VERSION 5.7 ;
BUSBITCHARS "[]" ;
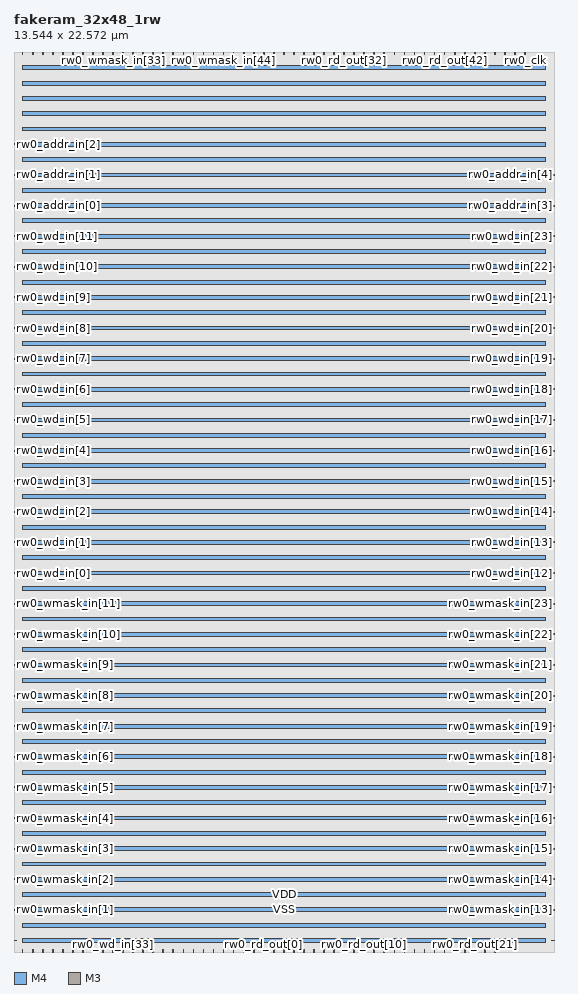
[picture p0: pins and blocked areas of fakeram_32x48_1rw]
MACRO fakeram_32x48_1rw
  FOREIGN fakeram_32x48_1rw 0 0 ;
  SYMMETRY X Y R90 ;
  SIZE 13.544 BY 22.572 ;
  CLASS BLOCK ;
  PIN rw0_wmask_in[0]
    DIRECTION INPUT ;
    USE SIGNAL ;
    SHAPE ABUTMENT ;
    PORT
      LAYER M4 ;
      RECT 0.000 0.276 0.072 0.300 ;
    END
  END rw0_wmask_in[0]
  PIN rw0_wmask_in[1]
    DIRECTION INPUT ;
    USE SIGNAL ;
    SHAPE ABUTMENT ;
    PORT
      LAYER M4 ;
      RECT 0.000 1.044 0.072 1.068 ;
    END
  END rw0_wmask_in[1]
  PIN rw0_wmask_in[2]
    DIRECTION INPUT ;
    USE SIGNAL ;
    SHAPE ABUTMENT ;
    PORT
      LAYER M4 ;
      RECT 0.000 1.812 0.072 1.836 ;
    END
  END rw0_wmask_in[2]
  PIN rw0_wmask_in[3]
    DIRECTION INPUT ;
    USE SIGNAL ;
    SHAPE ABUTMENT ;
    PORT
      LAYER M4 ;
      RECT 0.000 2.580 0.072 2.604 ;
    END
  END rw0_wmask_in[3]
  PIN rw0_wmask_in[4]
    DIRECTION INPUT ;
    USE SIGNAL ;
    SHAPE ABUTMENT ;
    PORT
      LAYER M4 ;
      RECT 0.000 3.348 0.072 3.372 ;
    END
  END rw0_wmask_in[4]
  PIN rw0_wmask_in[5]
    DIRECTION INPUT ;
    USE SIGNAL ;
    SHAPE ABUTMENT ;
    PORT
      LAYER M4 ;
      RECT 0.000 4.116 0.072 4.140 ;
    END
  END rw0_wmask_in[5]
  PIN rw0_wmask_in[6]
    DIRECTION INPUT ;
    USE SIGNAL ;
    SHAPE ABUTMENT ;
    PORT
      LAYER M4 ;
      RECT 0.000 4.884 0.072 4.908 ;
    END
  END rw0_wmask_in[6]
  PIN rw0_wmask_in[7]
    DIRECTION INPUT ;
    USE SIGNAL ;
    SHAPE ABUTMENT ;
    PORT
      LAYER M4 ;
      RECT 0.000 5.652 0.072 5.676 ;
    END
  END rw0_wmask_in[7]
  PIN rw0_wmask_in[8]
    DIRECTION INPUT ;
    USE SIGNAL ;
    SHAPE ABUTMENT ;
    PORT
      LAYER M4 ;
      RECT 0.000 6.420 0.072 6.444 ;
    END
  END rw0_wmask_in[8]
  PIN rw0_wmask_in[9]
    DIRECTION INPUT ;
    USE SIGNAL ;
    SHAPE ABUTMENT ;
    PORT
      LAYER M4 ;
      RECT 0.000 7.188 0.072 7.212 ;
    END
  END rw0_wmask_in[9]
  PIN rw0_wmask_in[10]
    DIRECTION INPUT ;
    USE SIGNAL ;
    SHAPE ABUTMENT ;
    PORT
      LAYER M4 ;
      RECT 0.000 7.956 0.072 7.980 ;
    END
  END rw0_wmask_in[10]
  PIN rw0_wmask_in[11]
    DIRECTION INPUT ;
    USE SIGNAL ;
    SHAPE ABUTMENT ;
    PORT
      LAYER M4 ;
      RECT 0.000 8.724 0.072 8.748 ;
    END
  END rw0_wmask_in[11]
  PIN rw0_wmask_in[12]
    DIRECTION INPUT ;
    USE SIGNAL ;
    SHAPE ABUTMENT ;
    PORT
      LAYER M4 ;
      RECT 13.472 0.276 13.544 0.300 ;
    END
  END rw0_wmask_in[12]
  PIN rw0_wmask_in[13]
    DIRECTION INPUT ;
    USE SIGNAL ;
    SHAPE ABUTMENT ;
    PORT
      LAYER M4 ;
      RECT 13.472 1.044 13.544 1.068 ;
    END
  END rw0_wmask_in[13]
  PIN rw0_wmask_in[14]
    DIRECTION INPUT ;
    USE SIGNAL ;
    SHAPE ABUTMENT ;
    PORT
      LAYER M4 ;
      RECT 13.472 1.812 13.544 1.836 ;
    END
  END rw0_wmask_in[14]
  PIN rw0_wmask_in[15]
    DIRECTION INPUT ;
    USE SIGNAL ;
    SHAPE ABUTMENT ;
    PORT
      LAYER M4 ;
      RECT 13.472 2.580 13.544 2.604 ;
    END
  END rw0_wmask_in[15]
  PIN rw0_wmask_in[16]
    DIRECTION INPUT ;
    USE SIGNAL ;
    SHAPE ABUTMENT ;
    PORT
      LAYER M4 ;
      RECT 13.472 3.348 13.544 3.372 ;
    END
  END rw0_wmask_in[16]
  PIN rw0_wmask_in[17]
    DIRECTION INPUT ;
    USE SIGNAL ;
    SHAPE ABUTMENT ;
    PORT
      LAYER M4 ;
      RECT 13.472 4.116 13.544 4.140 ;
    END
  END rw0_wmask_in[17]
  PIN rw0_wmask_in[18]
    DIRECTION INPUT ;
    USE SIGNAL ;
    SHAPE ABUTMENT ;
    PORT
      LAYER M4 ;
      RECT 13.472 4.884 13.544 4.908 ;
    END
  END rw0_wmask_in[18]
  PIN rw0_wmask_in[19]
    DIRECTION INPUT ;
    USE SIGNAL ;
    SHAPE ABUTMENT ;
    PORT
      LAYER M4 ;
      RECT 13.472 5.652 13.544 5.676 ;
    END
  END rw0_wmask_in[19]
  PIN rw0_wmask_in[20]
    DIRECTION INPUT ;
    USE SIGNAL ;
    SHAPE ABUTMENT ;
    PORT
      LAYER M4 ;
      RECT 13.472 6.420 13.544 6.444 ;
    END
  END rw0_wmask_in[20]
  PIN rw0_wmask_in[21]
    DIRECTION INPUT ;
    USE SIGNAL ;
    SHAPE ABUTMENT ;
    PORT
      LAYER M4 ;
      RECT 13.472 7.188 13.544 7.212 ;
    END
  END rw0_wmask_in[21]
  PIN rw0_wmask_in[22]
    DIRECTION INPUT ;
    USE SIGNAL ;
    SHAPE ABUTMENT ;
    PORT
      LAYER M4 ;
      RECT 13.472 7.956 13.544 7.980 ;
    END
  END rw0_wmask_in[22]
  PIN rw0_wmask_in[23]
    DIRECTION INPUT ;
    USE SIGNAL ;
    SHAPE ABUTMENT ;
    PORT
      LAYER M4 ;
      RECT 13.472 8.724 13.544 8.748 ;
    END
  END rw0_wmask_in[23]
  PIN rw0_wmask_in[24]
    DIRECTION INPUT ;
    USE SIGNAL ;
    SHAPE ABUTMENT ;
    PORT
      LAYER M3 ;
      RECT 0.207 22.518 0.225 22.572 ;
    END
  END rw0_wmask_in[24]
  PIN rw0_wmask_in[25]
    DIRECTION INPUT ;
    USE SIGNAL ;
    SHAPE ABUTMENT ;
    PORT
      LAYER M3 ;
      RECT 0.459 22.518 0.477 22.572 ;
    END
  END rw0_wmask_in[25]
  PIN rw0_wmask_in[26]
    DIRECTION INPUT ;
    USE SIGNAL ;
    SHAPE ABUTMENT ;
    PORT
      LAYER M3 ;
      RECT 0.711 22.518 0.729 22.572 ;
    END
  END rw0_wmask_in[26]
  PIN rw0_wmask_in[27]
    DIRECTION INPUT ;
    USE SIGNAL ;
    SHAPE ABUTMENT ;
    PORT
      LAYER M3 ;
      RECT 0.963 22.518 0.981 22.572 ;
    END
  END rw0_wmask_in[27]
  PIN rw0_wmask_in[28]
    DIRECTION INPUT ;
    USE SIGNAL ;
    SHAPE ABUTMENT ;
    PORT
      LAYER M3 ;
      RECT 1.215 22.518 1.233 22.572 ;
    END
  END rw0_wmask_in[28]
  PIN rw0_wmask_in[29]
    DIRECTION INPUT ;
    USE SIGNAL ;
    SHAPE ABUTMENT ;
    PORT
      LAYER M3 ;
      RECT 1.467 22.518 1.485 22.572 ;
    END
  END rw0_wmask_in[29]
  PIN rw0_wmask_in[30]
    DIRECTION INPUT ;
    USE SIGNAL ;
    SHAPE ABUTMENT ;
    PORT
      LAYER M3 ;
      RECT 1.719 22.518 1.737 22.572 ;
    END
  END rw0_wmask_in[30]
  PIN rw0_wmask_in[31]
    DIRECTION INPUT ;
    USE SIGNAL ;
    SHAPE ABUTMENT ;
    PORT
      LAYER M3 ;
      RECT 1.971 22.518 1.989 22.572 ;
    END
  END rw0_wmask_in[31]
  PIN rw0_wmask_in[32]
    DIRECTION INPUT ;
    USE SIGNAL ;
    SHAPE ABUTMENT ;
    PORT
      LAYER M3 ;
      RECT 2.223 22.518 2.241 22.572 ;
    END
  END rw0_wmask_in[32]
  PIN rw0_wmask_in[33]
    DIRECTION INPUT ;
    USE SIGNAL ;
    SHAPE ABUTMENT ;
    PORT
      LAYER M3 ;
      RECT 2.475 22.518 2.493 22.572 ;
    END
  END rw0_wmask_in[33]
  PIN rw0_wmask_in[34]
    DIRECTION INPUT ;
    USE SIGNAL ;
    SHAPE ABUTMENT ;
    PORT
      LAYER M3 ;
      RECT 2.727 22.518 2.745 22.572 ;
    END
  END rw0_wmask_in[34]
  PIN rw0_wmask_in[35]
    DIRECTION INPUT ;
    USE SIGNAL ;
    SHAPE ABUTMENT ;
    PORT
      LAYER M3 ;
      RECT 2.979 22.518 2.997 22.572 ;
    END
  END rw0_wmask_in[35]
  PIN rw0_wmask_in[36]
    DIRECTION INPUT ;
    USE SIGNAL ;
    SHAPE ABUTMENT ;
    PORT
      LAYER M3 ;
      RECT 3.231 22.518 3.249 22.572 ;
    END
  END rw0_wmask_in[36]
  PIN rw0_wmask_in[37]
    DIRECTION INPUT ;
    USE SIGNAL ;
    SHAPE ABUTMENT ;
    PORT
      LAYER M3 ;
      RECT 3.483 22.518 3.501 22.572 ;
    END
  END rw0_wmask_in[37]
  PIN rw0_wmask_in[38]
    DIRECTION INPUT ;
    USE SIGNAL ;
    SHAPE ABUTMENT ;
    PORT
      LAYER M3 ;
      RECT 3.735 22.518 3.753 22.572 ;
    END
  END rw0_wmask_in[38]
  PIN rw0_wmask_in[39]
    DIRECTION INPUT ;
    USE SIGNAL ;
    SHAPE ABUTMENT ;
    PORT
      LAYER M3 ;
      RECT 3.987 22.518 4.005 22.572 ;
    END
  END rw0_wmask_in[39]
  PIN rw0_wmask_in[40]
    DIRECTION INPUT ;
    USE SIGNAL ;
    SHAPE ABUTMENT ;
    PORT
      LAYER M3 ;
      RECT 4.239 22.518 4.257 22.572 ;
    END
  END rw0_wmask_in[40]
  PIN rw0_wmask_in[41]
    DIRECTION INPUT ;
    USE SIGNAL ;
    SHAPE ABUTMENT ;
    PORT
      LAYER M3 ;
      RECT 4.491 22.518 4.509 22.572 ;
    END
  END rw0_wmask_in[41]
  PIN rw0_wmask_in[42]
    DIRECTION INPUT ;
    USE SIGNAL ;
    SHAPE ABUTMENT ;
    PORT
      LAYER M3 ;
      RECT 4.743 22.518 4.761 22.572 ;
    END
  END rw0_wmask_in[42]
  PIN rw0_wmask_in[43]
    DIRECTION INPUT ;
    USE SIGNAL ;
    SHAPE ABUTMENT ;
    PORT
      LAYER M3 ;
      RECT 4.995 22.518 5.013 22.572 ;
    END
  END rw0_wmask_in[43]
  PIN rw0_wmask_in[44]
    DIRECTION INPUT ;
    USE SIGNAL ;
    SHAPE ABUTMENT ;
    PORT
      LAYER M3 ;
      RECT 5.247 22.518 5.265 22.572 ;
    END
  END rw0_wmask_in[44]
  PIN rw0_wmask_in[45]
    DIRECTION INPUT ;
    USE SIGNAL ;
    SHAPE ABUTMENT ;
    PORT
      LAYER M3 ;
      RECT 5.499 22.518 5.517 22.572 ;
    END
  END rw0_wmask_in[45]
  PIN rw0_wmask_in[46]
    DIRECTION INPUT ;
    USE SIGNAL ;
    SHAPE ABUTMENT ;
    PORT
      LAYER M3 ;
      RECT 5.751 22.518 5.769 22.572 ;
    END
  END rw0_wmask_in[46]
  PIN rw0_wmask_in[47]
    DIRECTION INPUT ;
    USE SIGNAL ;
    SHAPE ABUTMENT ;
    PORT
      LAYER M3 ;
      RECT 6.003 22.518 6.021 22.572 ;
    END
  END rw0_wmask_in[47]
  PIN rw0_wd_in[0]
    DIRECTION INPUT ;
    USE SIGNAL ;
    SHAPE ABUTMENT ;
    PORT
      LAYER M4 ;
      RECT 0.000 9.492 0.072 9.516 ;
    END
  END rw0_wd_in[0]
  PIN rw0_wd_in[1]
    DIRECTION INPUT ;
    USE SIGNAL ;
    SHAPE ABUTMENT ;
    PORT
      LAYER M4 ;
      RECT 0.000 10.260 0.072 10.284 ;
    END
  END rw0_wd_in[1]
  PIN rw0_wd_in[2]
    DIRECTION INPUT ;
    USE SIGNAL ;
    SHAPE ABUTMENT ;
    PORT
      LAYER M4 ;
      RECT 0.000 11.028 0.072 11.052 ;
    END
  END rw0_wd_in[2]
  PIN rw0_wd_in[3]
    DIRECTION INPUT ;
    USE SIGNAL ;
    SHAPE ABUTMENT ;
    PORT
      LAYER M4 ;
      RECT 0.000 11.796 0.072 11.820 ;
    END
  END rw0_wd_in[3]
  PIN rw0_wd_in[4]
    DIRECTION INPUT ;
    USE SIGNAL ;
    SHAPE ABUTMENT ;
    PORT
      LAYER M4 ;
      RECT 0.000 12.564 0.072 12.588 ;
    END
  END rw0_wd_in[4]
  PIN rw0_wd_in[5]
    DIRECTION INPUT ;
    USE SIGNAL ;
    SHAPE ABUTMENT ;
    PORT
      LAYER M4 ;
      RECT 0.000 13.332 0.072 13.356 ;
    END
  END rw0_wd_in[5]
  PIN rw0_wd_in[6]
    DIRECTION INPUT ;
    USE SIGNAL ;
    SHAPE ABUTMENT ;
    PORT
      LAYER M4 ;
      RECT 0.000 14.100 0.072 14.124 ;
    END
  END rw0_wd_in[6]
  PIN rw0_wd_in[7]
    DIRECTION INPUT ;
    USE SIGNAL ;
    SHAPE ABUTMENT ;
    PORT
      LAYER M4 ;
      RECT 0.000 14.868 0.072 14.892 ;
    END
  END rw0_wd_in[7]
  PIN rw0_wd_in[8]
    DIRECTION INPUT ;
    USE SIGNAL ;
    SHAPE ABUTMENT ;
    PORT
      LAYER M4 ;
      RECT 0.000 15.636 0.072 15.660 ;
    END
  END rw0_wd_in[8]
  PIN rw0_wd_in[9]
    DIRECTION INPUT ;
    USE SIGNAL ;
    SHAPE ABUTMENT ;
    PORT
      LAYER M4 ;
      RECT 0.000 16.404 0.072 16.428 ;
    END
  END rw0_wd_in[9]
  PIN rw0_wd_in[10]
    DIRECTION INPUT ;
    USE SIGNAL ;
    SHAPE ABUTMENT ;
    PORT
      LAYER M4 ;
      RECT 0.000 17.172 0.072 17.196 ;
    END
  END rw0_wd_in[10]
  PIN rw0_wd_in[11]
    DIRECTION INPUT ;
    USE SIGNAL ;
    SHAPE ABUTMENT ;
    PORT
      LAYER M4 ;
      RECT 0.000 17.940 0.072 17.964 ;
    END
  END rw0_wd_in[11]
  PIN rw0_wd_in[12]
    DIRECTION INPUT ;
    USE SIGNAL ;
    SHAPE ABUTMENT ;
    PORT
      LAYER M4 ;
      RECT 13.472 9.492 13.544 9.516 ;
    END
  END rw0_wd_in[12]
  PIN rw0_wd_in[13]
    DIRECTION INPUT ;
    USE SIGNAL ;
    SHAPE ABUTMENT ;
    PORT
      LAYER M4 ;
      RECT 13.472 10.260 13.544 10.284 ;
    END
  END rw0_wd_in[13]
  PIN rw0_wd_in[14]
    DIRECTION INPUT ;
    USE SIGNAL ;
    SHAPE ABUTMENT ;
    PORT
      LAYER M4 ;
      RECT 13.472 11.028 13.544 11.052 ;
    END
  END rw0_wd_in[14]
  PIN rw0_wd_in[15]
    DIRECTION INPUT ;
    USE SIGNAL ;
    SHAPE ABUTMENT ;
    PORT
      LAYER M4 ;
      RECT 13.472 11.796 13.544 11.820 ;
    END
  END rw0_wd_in[15]
  PIN rw0_wd_in[16]
    DIRECTION INPUT ;
    USE SIGNAL ;
    SHAPE ABUTMENT ;
    PORT
      LAYER M4 ;
      RECT 13.472 12.564 13.544 12.588 ;
    END
  END rw0_wd_in[16]
  PIN rw0_wd_in[17]
    DIRECTION INPUT ;
    USE SIGNAL ;
    SHAPE ABUTMENT ;
    PORT
      LAYER M4 ;
      RECT 13.472 13.332 13.544 13.356 ;
    END
  END rw0_wd_in[17]
  PIN rw0_wd_in[18]
    DIRECTION INPUT ;
    USE SIGNAL ;
    SHAPE ABUTMENT ;
    PORT
      LAYER M4 ;
      RECT 13.472 14.100 13.544 14.124 ;
    END
  END rw0_wd_in[18]
  PIN rw0_wd_in[19]
    DIRECTION INPUT ;
    USE SIGNAL ;
    SHAPE ABUTMENT ;
    PORT
      LAYER M4 ;
      RECT 13.472 14.868 13.544 14.892 ;
    END
  END rw0_wd_in[19]
  PIN rw0_wd_in[20]
    DIRECTION INPUT ;
    USE SIGNAL ;
    SHAPE ABUTMENT ;
    PORT
      LAYER M4 ;
      RECT 13.472 15.636 13.544 15.660 ;
    END
  END rw0_wd_in[20]
  PIN rw0_wd_in[21]
    DIRECTION INPUT ;
    USE SIGNAL ;
    SHAPE ABUTMENT ;
    PORT
      LAYER M4 ;
      RECT 13.472 16.404 13.544 16.428 ;
    END
  END rw0_wd_in[21]
  PIN rw0_wd_in[22]
    DIRECTION INPUT ;
    USE SIGNAL ;
    SHAPE ABUTMENT ;
    PORT
      LAYER M4 ;
      RECT 13.472 17.172 13.544 17.196 ;
    END
  END rw0_wd_in[22]
  PIN rw0_wd_in[23]
    DIRECTION INPUT ;
    USE SIGNAL ;
    SHAPE ABUTMENT ;
    PORT
      LAYER M4 ;
      RECT 13.472 17.940 13.544 17.964 ;
    END
  END rw0_wd_in[23]
  PIN rw0_wd_in[24]
    DIRECTION INPUT ;
    USE SIGNAL ;
    SHAPE ABUTMENT ;
    PORT
      LAYER M3 ;
      RECT 0.207 0.000 0.225 0.054 ;
    END
  END rw0_wd_in[24]
  PIN rw0_wd_in[25]
    DIRECTION INPUT ;
    USE SIGNAL ;
    SHAPE ABUTMENT ;
    PORT
      LAYER M3 ;
      RECT 0.459 0.000 0.477 0.054 ;
    END
  END rw0_wd_in[25]
  PIN rw0_wd_in[26]
    DIRECTION INPUT ;
    USE SIGNAL ;
    SHAPE ABUTMENT ;
    PORT
      LAYER M3 ;
      RECT 0.711 0.000 0.729 0.054 ;
    END
  END rw0_wd_in[26]
  PIN rw0_wd_in[27]
    DIRECTION INPUT ;
    USE SIGNAL ;
    SHAPE ABUTMENT ;
    PORT
      LAYER M3 ;
      RECT 0.963 0.000 0.981 0.054 ;
    END
  END rw0_wd_in[27]
  PIN rw0_wd_in[28]
    DIRECTION INPUT ;
    USE SIGNAL ;
    SHAPE ABUTMENT ;
    PORT
      LAYER M3 ;
      RECT 1.215 0.000 1.233 0.054 ;
    END
  END rw0_wd_in[28]
  PIN rw0_wd_in[29]
    DIRECTION INPUT ;
    USE SIGNAL ;
    SHAPE ABUTMENT ;
    PORT
      LAYER M3 ;
      RECT 1.467 0.000 1.485 0.054 ;
    END
  END rw0_wd_in[29]
  PIN rw0_wd_in[30]
    DIRECTION INPUT ;
    USE SIGNAL ;
    SHAPE ABUTMENT ;
    PORT
      LAYER M3 ;
      RECT 1.719 0.000 1.737 0.054 ;
    END
  END rw0_wd_in[30]
  PIN rw0_wd_in[31]
    DIRECTION INPUT ;
    USE SIGNAL ;
    SHAPE ABUTMENT ;
    PORT
      LAYER M3 ;
      RECT 1.971 0.000 1.989 0.054 ;
    END
  END rw0_wd_in[31]
  PIN rw0_wd_in[32]
    DIRECTION INPUT ;
    USE SIGNAL ;
    SHAPE ABUTMENT ;
    PORT
      LAYER M3 ;
      RECT 2.223 0.000 2.241 0.054 ;
    END
  END rw0_wd_in[32]
  PIN rw0_wd_in[33]
    DIRECTION INPUT ;
    USE SIGNAL ;
    SHAPE ABUTMENT ;
    PORT
      LAYER M3 ;
      RECT 2.475 0.000 2.493 0.054 ;
    END
  END rw0_wd_in[33]
  PIN rw0_wd_in[34]
    DIRECTION INPUT ;
    USE SIGNAL ;
    SHAPE ABUTMENT ;
    PORT
      LAYER M3 ;
      RECT 2.727 0.000 2.745 0.054 ;
    END
  END rw0_wd_in[34]
  PIN rw0_wd_in[35]
    DIRECTION INPUT ;
    USE SIGNAL ;
    SHAPE ABUTMENT ;
    PORT
      LAYER M3 ;
      RECT 2.979 0.000 2.997 0.054 ;
    END
  END rw0_wd_in[35]
  PIN rw0_wd_in[36]
    DIRECTION INPUT ;
    USE SIGNAL ;
    SHAPE ABUTMENT ;
    PORT
      LAYER M3 ;
      RECT 3.231 0.000 3.249 0.054 ;
    END
  END rw0_wd_in[36]
  PIN rw0_wd_in[37]
    DIRECTION INPUT ;
    USE SIGNAL ;
    SHAPE ABUTMENT ;
    PORT
      LAYER M3 ;
      RECT 3.483 0.000 3.501 0.054 ;
    END
  END rw0_wd_in[37]
  PIN rw0_wd_in[38]
    DIRECTION INPUT ;
    USE SIGNAL ;
    SHAPE ABUTMENT ;
    PORT
      LAYER M3 ;
      RECT 3.735 0.000 3.753 0.054 ;
    END
  END rw0_wd_in[38]
  PIN rw0_wd_in[39]
    DIRECTION INPUT ;
    USE SIGNAL ;
    SHAPE ABUTMENT ;
    PORT
      LAYER M3 ;
      RECT 3.987 0.000 4.005 0.054 ;
    END
  END rw0_wd_in[39]
  PIN rw0_wd_in[40]
    DIRECTION INPUT ;
    USE SIGNAL ;
    SHAPE ABUTMENT ;
    PORT
      LAYER M3 ;
      RECT 4.239 0.000 4.257 0.054 ;
    END
  END rw0_wd_in[40]
  PIN rw0_wd_in[41]
    DIRECTION INPUT ;
    USE SIGNAL ;
    SHAPE ABUTMENT ;
    PORT
      LAYER M3 ;
      RECT 4.491 0.000 4.509 0.054 ;
    END
  END rw0_wd_in[41]
  PIN rw0_wd_in[42]
    DIRECTION INPUT ;
    USE SIGNAL ;
    SHAPE ABUTMENT ;
    PORT
      LAYER M3 ;
      RECT 4.743 0.000 4.761 0.054 ;
    END
  END rw0_wd_in[42]
  PIN rw0_wd_in[43]
    DIRECTION INPUT ;
    USE SIGNAL ;
    SHAPE ABUTMENT ;
    PORT
      LAYER M3 ;
      RECT 4.995 0.000 5.013 0.054 ;
    END
  END rw0_wd_in[43]
  PIN rw0_wd_in[44]
    DIRECTION INPUT ;
    USE SIGNAL ;
    SHAPE ABUTMENT ;
    PORT
      LAYER M3 ;
      RECT 5.247 0.000 5.265 0.054 ;
    END
  END rw0_wd_in[44]
  PIN rw0_wd_in[45]
    DIRECTION INPUT ;
    USE SIGNAL ;
    SHAPE ABUTMENT ;
    PORT
      LAYER M3 ;
      RECT 5.499 0.000 5.517 0.054 ;
    END
  END rw0_wd_in[45]
  PIN rw0_wd_in[46]
    DIRECTION INPUT ;
    USE SIGNAL ;
    SHAPE ABUTMENT ;
    PORT
      LAYER M3 ;
      RECT 5.751 0.000 5.769 0.054 ;
    END
  END rw0_wd_in[46]
  PIN rw0_wd_in[47]
    DIRECTION INPUT ;
    USE SIGNAL ;
    SHAPE ABUTMENT ;
    PORT
      LAYER M3 ;
      RECT 6.003 0.000 6.021 0.054 ;
    END
  END rw0_wd_in[47]
  PIN rw0_rd_out[0]
    DIRECTION OUTPUT ;
    USE SIGNAL ;
    SHAPE ABUTMENT ;
    PORT
      LAYER M3 ;
      RECT 6.255 0.000 6.273 0.054 ;
    END
  END rw0_rd_out[0]
  PIN rw0_rd_out[1]
    DIRECTION OUTPUT ;
    USE SIGNAL ;
    SHAPE ABUTMENT ;
    PORT
      LAYER M3 ;
      RECT 6.507 0.000 6.525 0.054 ;
    END
  END rw0_rd_out[1]
  PIN rw0_rd_out[2]
    DIRECTION OUTPUT ;
    USE SIGNAL ;
    SHAPE ABUTMENT ;
    PORT
      LAYER M3 ;
      RECT 6.759 0.000 6.777 0.054 ;
    END
  END rw0_rd_out[2]
  PIN rw0_rd_out[3]
    DIRECTION OUTPUT ;
    USE SIGNAL ;
    SHAPE ABUTMENT ;
    PORT
      LAYER M3 ;
      RECT 7.011 0.000 7.029 0.054 ;
    END
  END rw0_rd_out[3]
  PIN rw0_rd_out[4]
    DIRECTION OUTPUT ;
    USE SIGNAL ;
    SHAPE ABUTMENT ;
    PORT
      LAYER M3 ;
      RECT 7.263 0.000 7.281 0.054 ;
    END
  END rw0_rd_out[4]
  PIN rw0_rd_out[5]
    DIRECTION OUTPUT ;
    USE SIGNAL ;
    SHAPE ABUTMENT ;
    PORT
      LAYER M3 ;
      RECT 7.515 0.000 7.533 0.054 ;
    END
  END rw0_rd_out[5]
  PIN rw0_rd_out[6]
    DIRECTION OUTPUT ;
    USE SIGNAL ;
    SHAPE ABUTMENT ;
    PORT
      LAYER M3 ;
      RECT 7.767 0.000 7.785 0.054 ;
    END
  END rw0_rd_out[6]
  PIN rw0_rd_out[7]
    DIRECTION OUTPUT ;
    USE SIGNAL ;
    SHAPE ABUTMENT ;
    PORT
      LAYER M3 ;
      RECT 8.019 0.000 8.037 0.054 ;
    END
  END rw0_rd_out[7]
  PIN rw0_rd_out[8]
    DIRECTION OUTPUT ;
    USE SIGNAL ;
    SHAPE ABUTMENT ;
    PORT
      LAYER M3 ;
      RECT 8.271 0.000 8.289 0.054 ;
    END
  END rw0_rd_out[8]
  PIN rw0_rd_out[9]
    DIRECTION OUTPUT ;
    USE SIGNAL ;
    SHAPE ABUTMENT ;
    PORT
      LAYER M3 ;
      RECT 8.523 0.000 8.541 0.054 ;
    END
  END rw0_rd_out[9]
  PIN rw0_rd_out[10]
    DIRECTION OUTPUT ;
    USE SIGNAL ;
    SHAPE ABUTMENT ;
    PORT
      LAYER M3 ;
      RECT 8.775 0.000 8.793 0.054 ;
    END
  END rw0_rd_out[10]
  PIN rw0_rd_out[11]
    DIRECTION OUTPUT ;
    USE SIGNAL ;
    SHAPE ABUTMENT ;
    PORT
      LAYER M3 ;
      RECT 9.027 0.000 9.045 0.054 ;
    END
  END rw0_rd_out[11]
  PIN rw0_rd_out[12]
    DIRECTION OUTPUT ;
    USE SIGNAL ;
    SHAPE ABUTMENT ;
    PORT
      LAYER M3 ;
      RECT 9.279 0.000 9.297 0.054 ;
    END
  END rw0_rd_out[12]
  PIN rw0_rd_out[13]
    DIRECTION OUTPUT ;
    USE SIGNAL ;
    SHAPE ABUTMENT ;
    PORT
      LAYER M3 ;
      RECT 9.531 0.000 9.549 0.054 ;
    END
  END rw0_rd_out[13]
  PIN rw0_rd_out[14]
    DIRECTION OUTPUT ;
    USE SIGNAL ;
    SHAPE ABUTMENT ;
    PORT
      LAYER M3 ;
      RECT 9.783 0.000 9.801 0.054 ;
    END
  END rw0_rd_out[14]
  PIN rw0_rd_out[15]
    DIRECTION OUTPUT ;
    USE SIGNAL ;
    SHAPE ABUTMENT ;
    PORT
      LAYER M3 ;
      RECT 10.035 0.000 10.053 0.054 ;
    END
  END rw0_rd_out[15]
  PIN rw0_rd_out[16]
    DIRECTION OUTPUT ;
    USE SIGNAL ;
    SHAPE ABUTMENT ;
    PORT
      LAYER M3 ;
      RECT 10.287 0.000 10.305 0.054 ;
    END
  END rw0_rd_out[16]
  PIN rw0_rd_out[17]
    DIRECTION OUTPUT ;
    USE SIGNAL ;
    SHAPE ABUTMENT ;
    PORT
      LAYER M3 ;
      RECT 10.539 0.000 10.557 0.054 ;
    END
  END rw0_rd_out[17]
  PIN rw0_rd_out[18]
    DIRECTION OUTPUT ;
    USE SIGNAL ;
    SHAPE ABUTMENT ;
    PORT
      LAYER M3 ;
      RECT 10.791 0.000 10.809 0.054 ;
    END
  END rw0_rd_out[18]
  PIN rw0_rd_out[19]
    DIRECTION OUTPUT ;
    USE SIGNAL ;
    SHAPE ABUTMENT ;
    PORT
      LAYER M3 ;
      RECT 11.043 0.000 11.061 0.054 ;
    END
  END rw0_rd_out[19]
  PIN rw0_rd_out[20]
    DIRECTION OUTPUT ;
    USE SIGNAL ;
    SHAPE ABUTMENT ;
    PORT
      LAYER M3 ;
      RECT 11.295 0.000 11.313 0.054 ;
    END
  END rw0_rd_out[20]
  PIN rw0_rd_out[21]
    DIRECTION OUTPUT ;
    USE SIGNAL ;
    SHAPE ABUTMENT ;
    PORT
      LAYER M3 ;
      RECT 11.547 0.000 11.565 0.054 ;
    END
  END rw0_rd_out[21]
  PIN rw0_rd_out[22]
    DIRECTION OUTPUT ;
    USE SIGNAL ;
    SHAPE ABUTMENT ;
    PORT
      LAYER M3 ;
      RECT 11.799 0.000 11.817 0.054 ;
    END
  END rw0_rd_out[22]
  PIN rw0_rd_out[23]
    DIRECTION OUTPUT ;
    USE SIGNAL ;
    SHAPE ABUTMENT ;
    PORT
      LAYER M3 ;
      RECT 12.051 0.000 12.069 0.054 ;
    END
  END rw0_rd_out[23]
  PIN rw0_rd_out[24]
    DIRECTION OUTPUT ;
    USE SIGNAL ;
    SHAPE ABUTMENT ;
    PORT
      LAYER M3 ;
      RECT 6.255 22.518 6.273 22.572 ;
    END
  END rw0_rd_out[24]
  PIN rw0_rd_out[25]
    DIRECTION OUTPUT ;
    USE SIGNAL ;
    SHAPE ABUTMENT ;
    PORT
      LAYER M3 ;
      RECT 6.507 22.518 6.525 22.572 ;
    END
  END rw0_rd_out[25]
  PIN rw0_rd_out[26]
    DIRECTION OUTPUT ;
    USE SIGNAL ;
    SHAPE ABUTMENT ;
    PORT
      LAYER M3 ;
      RECT 6.759 22.518 6.777 22.572 ;
    END
  END rw0_rd_out[26]
  PIN rw0_rd_out[27]
    DIRECTION OUTPUT ;
    USE SIGNAL ;
    SHAPE ABUTMENT ;
    PORT
      LAYER M3 ;
      RECT 7.011 22.518 7.029 22.572 ;
    END
  END rw0_rd_out[27]
  PIN rw0_rd_out[28]
    DIRECTION OUTPUT ;
    USE SIGNAL ;
    SHAPE ABUTMENT ;
    PORT
      LAYER M3 ;
      RECT 7.263 22.518 7.281 22.572 ;
    END
  END rw0_rd_out[28]
  PIN rw0_rd_out[29]
    DIRECTION OUTPUT ;
    USE SIGNAL ;
    SHAPE ABUTMENT ;
    PORT
      LAYER M3 ;
      RECT 7.515 22.518 7.533 22.572 ;
    END
  END rw0_rd_out[29]
  PIN rw0_rd_out[30]
    DIRECTION OUTPUT ;
    USE SIGNAL ;
    SHAPE ABUTMENT ;
    PORT
      LAYER M3 ;
      RECT 7.767 22.518 7.785 22.572 ;
    END
  END rw0_rd_out[30]
  PIN rw0_rd_out[31]
    DIRECTION OUTPUT ;
    USE SIGNAL ;
    SHAPE ABUTMENT ;
    PORT
      LAYER M3 ;
      RECT 8.019 22.518 8.037 22.572 ;
    END
  END rw0_rd_out[31]
  PIN rw0_rd_out[32]
    DIRECTION OUTPUT ;
    USE SIGNAL ;
    SHAPE ABUTMENT ;
    PORT
      LAYER M3 ;
      RECT 8.271 22.518 8.289 22.572 ;
    END
  END rw0_rd_out[32]
  PIN rw0_rd_out[33]
    DIRECTION OUTPUT ;
    USE SIGNAL ;
    SHAPE ABUTMENT ;
    PORT
      LAYER M3 ;
      RECT 8.523 22.518 8.541 22.572 ;
    END
  END rw0_rd_out[33]
  PIN rw0_rd_out[34]
    DIRECTION OUTPUT ;
    USE SIGNAL ;
    SHAPE ABUTMENT ;
    PORT
      LAYER M3 ;
      RECT 8.775 22.518 8.793 22.572 ;
    END
  END rw0_rd_out[34]
  PIN rw0_rd_out[35]
    DIRECTION OUTPUT ;
    USE SIGNAL ;
    SHAPE ABUTMENT ;
    PORT
      LAYER M3 ;
      RECT 9.027 22.518 9.045 22.572 ;
    END
  END rw0_rd_out[35]
  PIN rw0_rd_out[36]
    DIRECTION OUTPUT ;
    USE SIGNAL ;
    SHAPE ABUTMENT ;
    PORT
      LAYER M3 ;
      RECT 9.279 22.518 9.297 22.572 ;
    END
  END rw0_rd_out[36]
  PIN rw0_rd_out[37]
    DIRECTION OUTPUT ;
    USE SIGNAL ;
    SHAPE ABUTMENT ;
    PORT
      LAYER M3 ;
      RECT 9.531 22.518 9.549 22.572 ;
    END
  END rw0_rd_out[37]
  PIN rw0_rd_out[38]
    DIRECTION OUTPUT ;
    USE SIGNAL ;
    SHAPE ABUTMENT ;
    PORT
      LAYER M3 ;
      RECT 9.783 22.518 9.801 22.572 ;
    END
  END rw0_rd_out[38]
  PIN rw0_rd_out[39]
    DIRECTION OUTPUT ;
    USE SIGNAL ;
    SHAPE ABUTMENT ;
    PORT
      LAYER M3 ;
      RECT 10.035 22.518 10.053 22.572 ;
    END
  END rw0_rd_out[39]
  PIN rw0_rd_out[40]
    DIRECTION OUTPUT ;
    USE SIGNAL ;
    SHAPE ABUTMENT ;
    PORT
      LAYER M3 ;
      RECT 10.287 22.518 10.305 22.572 ;
    END
  END rw0_rd_out[40]
  PIN rw0_rd_out[41]
    DIRECTION OUTPUT ;
    USE SIGNAL ;
    SHAPE ABUTMENT ;
    PORT
      LAYER M3 ;
      RECT 10.539 22.518 10.557 22.572 ;
    END
  END rw0_rd_out[41]
  PIN rw0_rd_out[42]
    DIRECTION OUTPUT ;
    USE SIGNAL ;
    SHAPE ABUTMENT ;
    PORT
      LAYER M3 ;
      RECT 10.791 22.518 10.809 22.572 ;
    END
  END rw0_rd_out[42]
  PIN rw0_rd_out[43]
    DIRECTION OUTPUT ;
    USE SIGNAL ;
    SHAPE ABUTMENT ;
    PORT
      LAYER M3 ;
      RECT 11.043 22.518 11.061 22.572 ;
    END
  END rw0_rd_out[43]
  PIN rw0_rd_out[44]
    DIRECTION OUTPUT ;
    USE SIGNAL ;
    SHAPE ABUTMENT ;
    PORT
      LAYER M3 ;
      RECT 11.295 22.518 11.313 22.572 ;
    END
  END rw0_rd_out[44]
  PIN rw0_rd_out[45]
    DIRECTION OUTPUT ;
    USE SIGNAL ;
    SHAPE ABUTMENT ;
    PORT
      LAYER M3 ;
      RECT 11.547 22.518 11.565 22.572 ;
    END
  END rw0_rd_out[45]
  PIN rw0_rd_out[46]
    DIRECTION OUTPUT ;
    USE SIGNAL ;
    SHAPE ABUTMENT ;
    PORT
      LAYER M3 ;
      RECT 11.799 22.518 11.817 22.572 ;
    END
  END rw0_rd_out[46]
  PIN rw0_rd_out[47]
    DIRECTION OUTPUT ;
    USE SIGNAL ;
    SHAPE ABUTMENT ;
    PORT
      LAYER M3 ;
      RECT 12.051 22.518 12.069 22.572 ;
    END
  END rw0_rd_out[47]
  PIN rw0_addr_in[0]
    DIRECTION INPUT ;
    USE SIGNAL ;
    SHAPE ABUTMENT ;
    PORT
      LAYER M4 ;
      RECT 0.000 18.708 0.072 18.732 ;
    END
  END rw0_addr_in[0]
  PIN rw0_addr_in[1]
    DIRECTION INPUT ;
    USE SIGNAL ;
    SHAPE ABUTMENT ;
    PORT
      LAYER M4 ;
      RECT 0.000 19.476 0.072 19.500 ;
    END
  END rw0_addr_in[1]
  PIN rw0_addr_in[2]
    DIRECTION INPUT ;
    USE SIGNAL ;
    SHAPE ABUTMENT ;
    PORT
      LAYER M4 ;
      RECT 0.000 20.244 0.072 20.268 ;
    END
  END rw0_addr_in[2]
  PIN rw0_addr_in[3]
    DIRECTION INPUT ;
    USE SIGNAL ;
    SHAPE ABUTMENT ;
    PORT
      LAYER M4 ;
      RECT 13.472 18.708 13.544 18.732 ;
    END
  END rw0_addr_in[3]
  PIN rw0_addr_in[4]
    DIRECTION INPUT ;
    USE SIGNAL ;
    SHAPE ABUTMENT ;
    PORT
      LAYER M4 ;
      RECT 13.472 19.476 13.544 19.500 ;
    END
  END rw0_addr_in[4]
  PIN rw0_we_in
    DIRECTION INPUT ;
    USE SIGNAL ;
    SHAPE ABUTMENT ;
    PORT
      LAYER M3 ;
      RECT 12.303 22.518 12.321 22.572 ;
    END
  END rw0_we_in
  PIN rw0_ce_in
    DIRECTION INPUT ;
    USE SIGNAL ;
    SHAPE ABUTMENT ;
    PORT
      LAYER M3 ;
      RECT 12.555 22.518 12.573 22.572 ;
    END
  END rw0_ce_in
  PIN rw0_clk
    DIRECTION INPUT ;
    USE SIGNAL ;
    SHAPE ABUTMENT ;
    PORT
      LAYER M3 ;
      RECT 12.807 22.518 12.825 22.572 ;
    END
  END rw0_clk
  PIN VSS
    DIRECTION INOUT ;
    USE GROUND ;
    PORT
      LAYER M4 ;
      RECT 0.216 0.240 13.328 0.336 ;
      RECT 0.216 1.008 13.328 1.104 ;
      RECT 0.216 1.776 13.328 1.872 ;
      RECT 0.216 2.544 13.328 2.640 ;
      RECT 0.216 3.312 13.328 3.408 ;
      RECT 0.216 4.080 13.328 4.176 ;
      RECT 0.216 4.848 13.328 4.944 ;
      RECT 0.216 5.616 13.328 5.712 ;
      RECT 0.216 6.384 13.328 6.480 ;
      RECT 0.216 7.152 13.328 7.248 ;
      RECT 0.216 7.920 13.328 8.016 ;
      RECT 0.216 8.688 13.328 8.784 ;
      RECT 0.216 9.456 13.328 9.552 ;
      RECT 0.216 10.224 13.328 10.320 ;
      RECT 0.216 10.992 13.328 11.088 ;
      RECT 0.216 11.760 13.328 11.856 ;
      RECT 0.216 12.528 13.328 12.624 ;
      RECT 0.216 13.296 13.328 13.392 ;
      RECT 0.216 14.064 13.328 14.160 ;
      RECT 0.216 14.832 13.328 14.928 ;
      RECT 0.216 15.600 13.328 15.696 ;
      RECT 0.216 16.368 13.328 16.464 ;
      RECT 0.216 17.136 13.328 17.232 ;
      RECT 0.216 17.904 13.328 18.000 ;
      RECT 0.216 18.672 13.328 18.768 ;
      RECT 0.216 19.440 13.328 19.536 ;
      RECT 0.216 20.208 13.328 20.304 ;
      RECT 0.216 20.976 13.328 21.072 ;
      RECT 0.216 21.744 13.328 21.840 ;
    END
  END VSS
  PIN VDD
    DIRECTION INOUT ;
    USE POWER ;
    PORT
      LAYER M4 ;
      RECT 0.216 0.624 13.328 0.720 ;
      RECT 0.216 1.392 13.328 1.488 ;
      RECT 0.216 2.160 13.328 2.256 ;
      RECT 0.216 2.928 13.328 3.024 ;
      RECT 0.216 3.696 13.328 3.792 ;
      RECT 0.216 4.464 13.328 4.560 ;
      RECT 0.216 5.232 13.328 5.328 ;
      RECT 0.216 6.000 13.328 6.096 ;
      RECT 0.216 6.768 13.328 6.864 ;
      RECT 0.216 7.536 13.328 7.632 ;
      RECT 0.216 8.304 13.328 8.400 ;
      RECT 0.216 9.072 13.328 9.168 ;
      RECT 0.216 9.840 13.328 9.936 ;
      RECT 0.216 10.608 13.328 10.704 ;
      RECT 0.216 11.376 13.328 11.472 ;
      RECT 0.216 12.144 13.328 12.240 ;
      RECT 0.216 12.912 13.328 13.008 ;
      RECT 0.216 13.680 13.328 13.776 ;
      RECT 0.216 14.448 13.328 14.544 ;
      RECT 0.216 15.216 13.328 15.312 ;
      RECT 0.216 15.984 13.328 16.080 ;
      RECT 0.216 16.752 13.328 16.848 ;
      RECT 0.216 17.520 13.328 17.616 ;
      RECT 0.216 18.288 13.328 18.384 ;
      RECT 0.216 19.056 13.328 19.152 ;
      RECT 0.216 19.824 13.328 19.920 ;
      RECT 0.216 20.592 13.328 20.688 ;
      RECT 0.216 21.360 13.328 21.456 ;
      RECT 0.216 22.128 13.328 22.224 ;
    END
  END VDD
  OBS
    LAYER M1 ;
    RECT 0 0 13.544 22.572 ;
    LAYER M2 ;
    RECT 0 0 13.544 22.572 ;
    LAYER M3 ;
    RECT 0 0 13.544 22.572 ;
    LAYER M4 ;
    RECT 0 0 13.544 22.572 ;
  END
END fakeram_32x48_1rw

END LIBRARY
